VERSION 5.7 ;
BUSBITCHARS "[]" ;
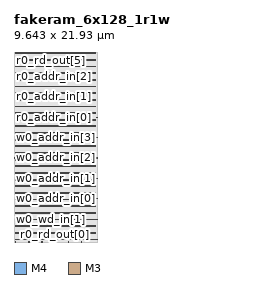
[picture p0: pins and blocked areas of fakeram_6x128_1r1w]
MACRO fakeram_6x128_1r1w
  FOREIGN fakeram_6x128_1r1w 0 0 ;
  SYMMETRY X Y R90 ;
  SIZE 9.643 BY 21.930 ;
  CLASS BLOCK ;
  PIN w0_wd_in[0]
    DIRECTION INPUT ;
    USE SIGNAL ;
    SHAPE ABUTMENT ;
    PORT
      LAYER M4 ;
      RECT 0.000 0.276 0.072 0.300 ;
    END
  END w0_wd_in[0]
  PIN w0_wd_in[1]
    DIRECTION INPUT ;
    USE SIGNAL ;
    SHAPE ABUTMENT ;
    PORT
      LAYER M4 ;
      RECT 0.000 2.628 0.072 2.652 ;
    END
  END w0_wd_in[1]
  PIN w0_wd_in[2]
    DIRECTION INPUT ;
    USE SIGNAL ;
    SHAPE ABUTMENT ;
    PORT
      LAYER M4 ;
      RECT 9.571 0.276 9.643 0.300 ;
    END
  END w0_wd_in[2]
  PIN w0_wd_in[3]
    DIRECTION OUTPUT ;
    USE SIGNAL ;
    SHAPE ABUTMENT ;
    PORT
      LAYER M3 ;
      RECT 0.207 0.000 0.225 0.054 ;
    END
  END w0_wd_in[3]
  PIN w0_wd_in[4]
    DIRECTION OUTPUT ;
    USE SIGNAL ;
    SHAPE ABUTMENT ;
    PORT
      LAYER M3 ;
      RECT 1.719 0.000 1.737 0.054 ;
    END
  END w0_wd_in[4]
  PIN w0_wd_in[5]
    DIRECTION OUTPUT ;
    USE SIGNAL ;
    SHAPE ABUTMENT ;
    PORT
      LAYER M3 ;
      RECT 3.231 0.000 3.249 0.054 ;
    END
  END w0_wd_in[5]
  PIN r0_rd_out[0]
    DIRECTION OUTPUT ;
    USE SIGNAL ;
    SHAPE ABUTMENT ;
    PORT
      LAYER M3 ;
      RECT 4.743 0.000 4.761 0.054 ;
    END
  END r0_rd_out[0]
  PIN r0_rd_out[1]
    DIRECTION OUTPUT ;
    USE SIGNAL ;
    SHAPE ABUTMENT ;
    PORT
      LAYER M3 ;
      RECT 6.255 0.000 6.273 0.054 ;
    END
  END r0_rd_out[1]
  PIN r0_rd_out[2]
    DIRECTION OUTPUT ;
    USE SIGNAL ;
    SHAPE ABUTMENT ;
    PORT
      LAYER M3 ;
      RECT 7.767 0.000 7.785 0.054 ;
    END
  END r0_rd_out[2]
  PIN r0_rd_out[3]
    DIRECTION OUTPUT ;
    USE SIGNAL ;
    SHAPE ABUTMENT ;
    PORT
      LAYER M3 ;
      RECT 0.207 21.876 0.225 21.930 ;
    END
  END r0_rd_out[3]
  PIN r0_rd_out[4]
    DIRECTION OUTPUT ;
    USE SIGNAL ;
    SHAPE ABUTMENT ;
    PORT
      LAYER M3 ;
      RECT 1.323 21.876 1.341 21.930 ;
    END
  END r0_rd_out[4]
  PIN r0_rd_out[5]
    DIRECTION OUTPUT ;
    USE SIGNAL ;
    SHAPE ABUTMENT ;
    PORT
      LAYER M3 ;
      RECT 2.439 21.876 2.457 21.930 ;
    END
  END r0_rd_out[5]
  PIN w0_addr_in[0]
    DIRECTION INPUT ;
    USE SIGNAL ;
    SHAPE ABUTMENT ;
    PORT
      LAYER M4 ;
      RECT 0.000 4.980 0.072 5.004 ;
    END
  END w0_addr_in[0]
  PIN w0_addr_in[1]
    DIRECTION INPUT ;
    USE SIGNAL ;
    SHAPE ABUTMENT ;
    PORT
      LAYER M4 ;
      RECT 0.000 7.332 0.072 7.356 ;
    END
  END w0_addr_in[1]
  PIN w0_addr_in[2]
    DIRECTION INPUT ;
    USE SIGNAL ;
    SHAPE ABUTMENT ;
    PORT
      LAYER M4 ;
      RECT 0.000 9.684 0.072 9.708 ;
    END
  END w0_addr_in[2]
  PIN w0_addr_in[3]
    DIRECTION INPUT ;
    USE SIGNAL ;
    SHAPE ABUTMENT ;
    PORT
      LAYER M4 ;
      RECT 0.000 12.036 0.072 12.060 ;
    END
  END w0_addr_in[3]
  PIN w0_addr_in[4]
    DIRECTION INPUT ;
    USE SIGNAL ;
    SHAPE ABUTMENT ;
    PORT
      LAYER M4 ;
      RECT 9.571 2.628 9.643 2.652 ;
    END
  END w0_addr_in[4]
  PIN w0_addr_in[5]
    DIRECTION INPUT ;
    USE SIGNAL ;
    SHAPE ABUTMENT ;
    PORT
      LAYER M4 ;
      RECT 9.571 4.980 9.643 5.004 ;
    END
  END w0_addr_in[5]
  PIN w0_addr_in[6]
    DIRECTION INPUT ;
    USE SIGNAL ;
    SHAPE ABUTMENT ;
    PORT
      LAYER M4 ;
      RECT 9.571 7.332 9.643 7.356 ;
    END
  END w0_addr_in[6]
  PIN r0_addr_in[0]
    DIRECTION INPUT ;
    USE SIGNAL ;
    SHAPE ABUTMENT ;
    PORT
      LAYER M4 ;
      RECT 0.000 14.388 0.072 14.412 ;
    END
  END r0_addr_in[0]
  PIN r0_addr_in[1]
    DIRECTION INPUT ;
    USE SIGNAL ;
    SHAPE ABUTMENT ;
    PORT
      LAYER M4 ;
      RECT 0.000 16.740 0.072 16.764 ;
    END
  END r0_addr_in[1]
  PIN r0_addr_in[2]
    DIRECTION INPUT ;
    USE SIGNAL ;
    SHAPE ABUTMENT ;
    PORT
      LAYER M4 ;
      RECT 0.000 19.092 0.072 19.116 ;
    END
  END r0_addr_in[2]
  PIN r0_addr_in[3]
    DIRECTION INPUT ;
    USE SIGNAL ;
    SHAPE ABUTMENT ;
    PORT
      LAYER M4 ;
      RECT 0.000 21.444 0.072 21.468 ;
    END
  END r0_addr_in[3]
  PIN r0_addr_in[4]
    DIRECTION INPUT ;
    USE SIGNAL ;
    SHAPE ABUTMENT ;
    PORT
      LAYER M4 ;
      RECT 9.571 9.684 9.643 9.708 ;
    END
  END r0_addr_in[4]
  PIN r0_addr_in[5]
    DIRECTION INPUT ;
    USE SIGNAL ;
    SHAPE ABUTMENT ;
    PORT
      LAYER M4 ;
      RECT 9.571 12.036 9.643 12.060 ;
    END
  END r0_addr_in[5]
  PIN r0_addr_in[6]
    DIRECTION INPUT ;
    USE SIGNAL ;
    SHAPE ABUTMENT ;
    PORT
      LAYER M4 ;
      RECT 9.571 14.388 9.643 14.412 ;
    END
  END r0_addr_in[6]
  PIN w0_we_in
    DIRECTION INPUT ;
    USE SIGNAL ;
    SHAPE ABUTMENT ;
    PORT
      LAYER M3 ;
      RECT 3.555 21.876 3.573 21.930 ;
    END
  END w0_we_in
  PIN w0_ce_in
    DIRECTION INPUT ;
    USE SIGNAL ;
    SHAPE ABUTMENT ;
    PORT
      LAYER M3 ;
      RECT 4.671 21.876 4.689 21.930 ;
    END
  END w0_ce_in
  PIN w0_clk
    DIRECTION INPUT ;
    USE SIGNAL ;
    SHAPE ABUTMENT ;
    PORT
      LAYER M3 ;
      RECT 5.787 21.876 5.805 21.930 ;
    END
  END w0_clk
  PIN r0_ce_in
    DIRECTION INPUT ;
    USE SIGNAL ;
    SHAPE ABUTMENT ;
    PORT
      LAYER M3 ;
      RECT 6.903 21.876 6.921 21.930 ;
    END
  END r0_ce_in
  PIN r0_clk
    DIRECTION INPUT ;
    USE SIGNAL ;
    SHAPE ABUTMENT ;
    PORT
      LAYER M3 ;
      RECT 8.019 21.876 8.037 21.930 ;
    END
  END r0_clk
  PIN VSS
    DIRECTION INOUT ;
    USE GROUND ;
    PORT
      LAYER M4 ;
      RECT 0.216 0.240 9.427 0.336 ;
      RECT 0.216 1.008 9.427 1.104 ;
      RECT 0.216 1.776 9.427 1.872 ;
      RECT 0.216 2.544 9.427 2.640 ;
      RECT 0.216 3.312 9.427 3.408 ;
      RECT 0.216 4.080 9.427 4.176 ;
      RECT 0.216 4.848 9.427 4.944 ;
      RECT 0.216 5.616 9.427 5.712 ;
      RECT 0.216 6.384 9.427 6.480 ;
      RECT 0.216 7.152 9.427 7.248 ;
      RECT 0.216 7.920 9.427 8.016 ;
      RECT 0.216 8.688 9.427 8.784 ;
      RECT 0.216 9.456 9.427 9.552 ;
      RECT 0.216 10.224 9.427 10.320 ;
      RECT 0.216 10.992 9.427 11.088 ;
      RECT 0.216 11.760 9.427 11.856 ;
      RECT 0.216 12.528 9.427 12.624 ;
      RECT 0.216 13.296 9.427 13.392 ;
      RECT 0.216 14.064 9.427 14.160 ;
      RECT 0.216 14.832 9.427 14.928 ;
      RECT 0.216 15.600 9.427 15.696 ;
      RECT 0.216 16.368 9.427 16.464 ;
      RECT 0.216 17.136 9.427 17.232 ;
      RECT 0.216 17.904 9.427 18.000 ;
      RECT 0.216 18.672 9.427 18.768 ;
      RECT 0.216 19.440 9.427 19.536 ;
      RECT 0.216 20.208 9.427 20.304 ;
      RECT 0.216 20.976 9.427 21.072 ;
      RECT 0.216 21.744 9.427 21.840 ;
    END
  END VSS
  PIN VDD
    DIRECTION INOUT ;
    USE POWER ;
    PORT
      LAYER M4 ;
      RECT 0.216 0.240 9.427 0.336 ;
      RECT 0.216 1.008 9.427 1.104 ;
      RECT 0.216 1.776 9.427 1.872 ;
      RECT 0.216 2.544 9.427 2.640 ;
      RECT 0.216 3.312 9.427 3.408 ;
      RECT 0.216 4.080 9.427 4.176 ;
      RECT 0.216 4.848 9.427 4.944 ;
      RECT 0.216 5.616 9.427 5.712 ;
      RECT 0.216 6.384 9.427 6.480 ;
      RECT 0.216 7.152 9.427 7.248 ;
      RECT 0.216 7.920 9.427 8.016 ;
      RECT 0.216 8.688 9.427 8.784 ;
      RECT 0.216 9.456 9.427 9.552 ;
      RECT 0.216 10.224 9.427 10.320 ;
      RECT 0.216 10.992 9.427 11.088 ;
      RECT 0.216 11.760 9.427 11.856 ;
      RECT 0.216 12.528 9.427 12.624 ;
      RECT 0.216 13.296 9.427 13.392 ;
      RECT 0.216 14.064 9.427 14.160 ;
      RECT 0.216 14.832 9.427 14.928 ;
      RECT 0.216 15.600 9.427 15.696 ;
      RECT 0.216 16.368 9.427 16.464 ;
      RECT 0.216 17.136 9.427 17.232 ;
      RECT 0.216 17.904 9.427 18.000 ;
      RECT 0.216 18.672 9.427 18.768 ;
      RECT 0.216 19.440 9.427 19.536 ;
      RECT 0.216 20.208 9.427 20.304 ;
      RECT 0.216 20.976 9.427 21.072 ;
      RECT 0.216 21.744 9.427 21.840 ;
    END
  END VDD
  OBS
    LAYER M1 ;
    RECT 0 0 9.643 21.930 ;
    LAYER M2 ;
    RECT 0 0 9.643 21.930 ;
    LAYER M3 ;
    RECT 0 0 9.643 21.930 ;
    LAYER M4 ;
    RECT 0 0 9.643 21.930 ;
  END
END fakeram_6x128_1r1w

END LIBRARY
